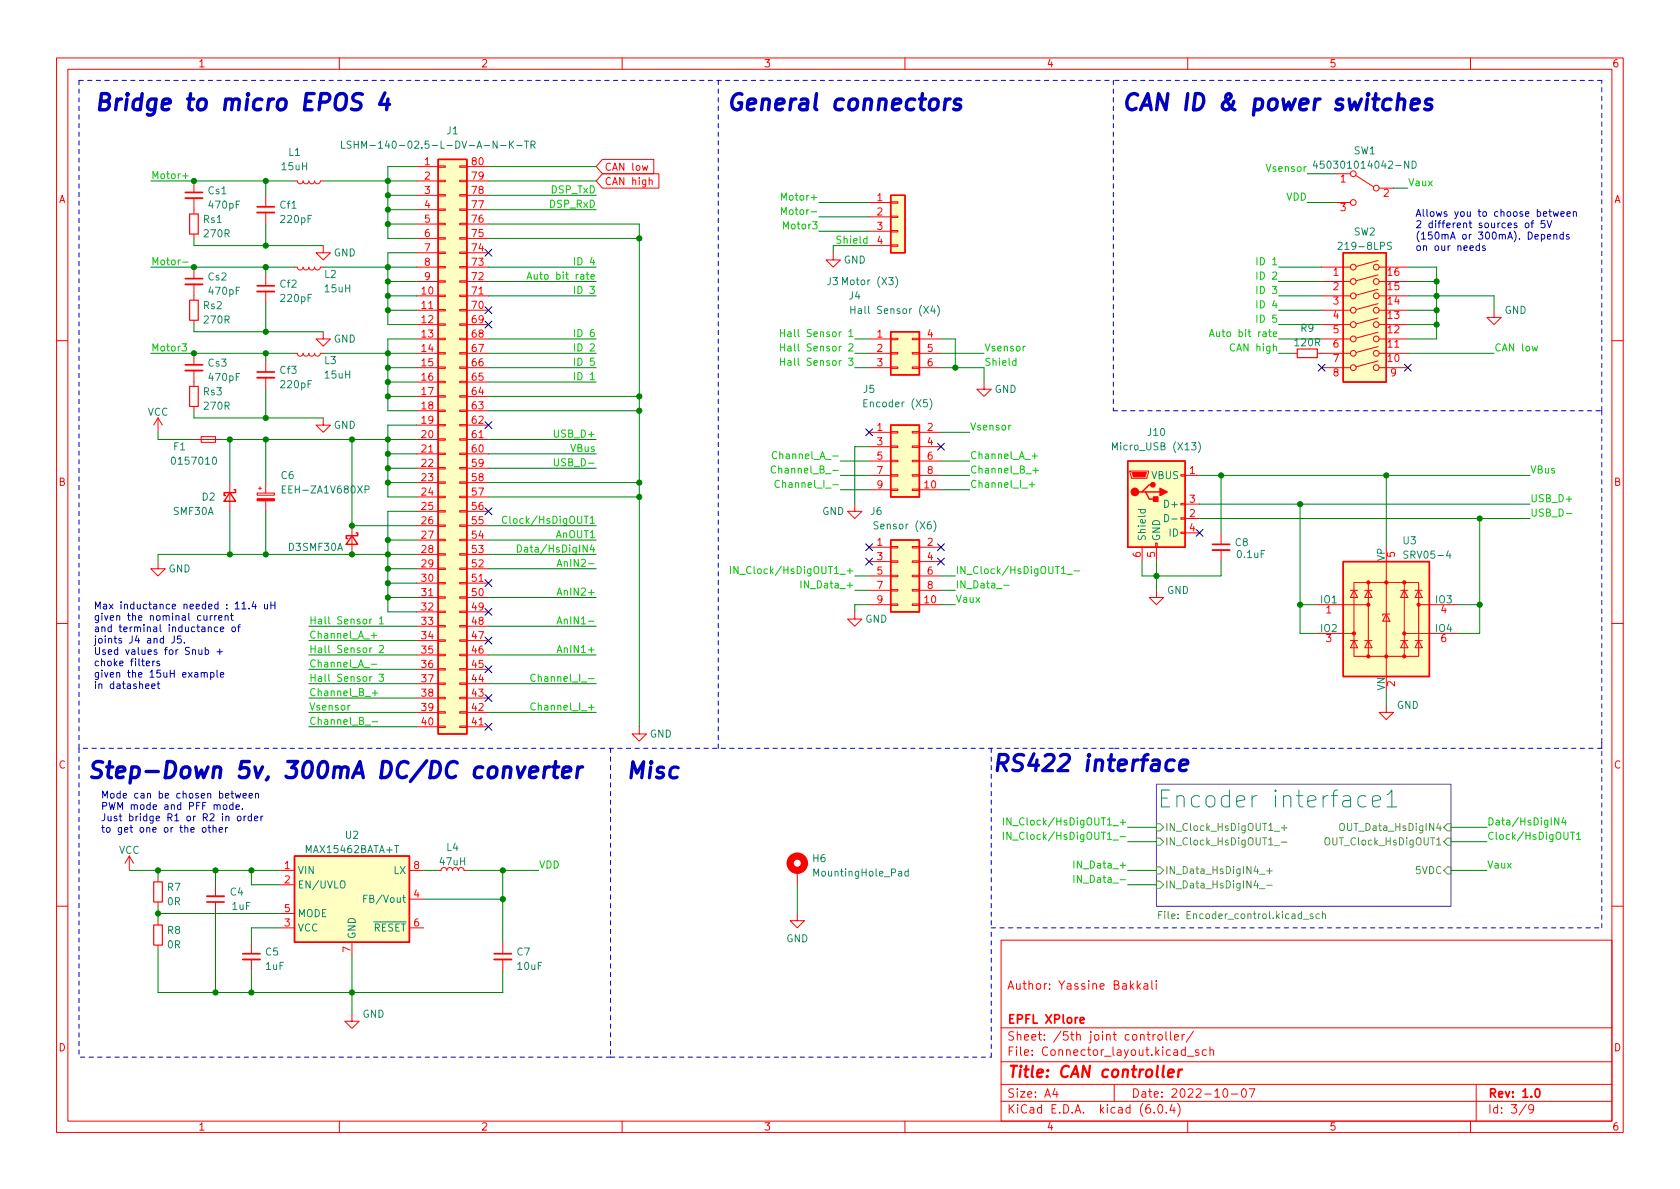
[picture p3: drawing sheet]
<svg xmlns="http://www.w3.org/2000/svg" width="297mm" height="210mm" viewBox="0 0 297 210" stroke-linecap="round" stroke-linejoin="round" font-family="sans-serif">
<defs><g id="words">
<text font-size="4.2" fill="#008484" x="207.3" y="142.8">Encoder interface1</text>
<g font-size="4" fill="#0000c2">
<text x="16.5" y="19.5">Bridge to micro EPOS 4</text>
<text x="128.3" y="19.5">General connectors</text>
<text x="198.1" y="19.5">CAN ID &amp; power switches</text>
<text x="15.2" y="137.7">Step-Down 5v, 300mA DC/DC converter</text>
<text x="110.5" y="137.7">Misc</text>
<text x="175.3" y="136.4">RS422 interface</text>
</g>
<text font-size="2.8" fill="#f00" x="178" y="190.6">Title: CAN controller</text>
<g font-size="2.1" fill="#f00">
<text x="178" y="175">Author: Yassine Bakkali</text>
<text x="178" y="184">Sheet: /5th joint controller/</text>
<text x="178" y="181">EPFL XPlore</text>
<text x="178" y="186.7">File: Connector_layout.kicad_sch</text>
<text x="178" y="196.9">KiCad E.D.A. kicad (6.0.4)</text>
<text x="178" y="194.1">Size: A4</text>
<text x="200" y="194.1">Date: 2022-10-07</text>
<text x="263" y="194.1">Rev: 1.0</text>
<text x="263" y="196.9">Id: 3/9</text>
</g>
<g font-size="1.8" fill="#f00">
<text x="35" y="11.9">1</text>
<text x="85" y="11.9">2</text>
<text x="135" y="11.9">3</text>
<text x="185" y="11.9">4</text>
<text x="235" y="11.9">5</text>
<text x="285" y="11.9">6</text>
<text x="75.1" y="29.2">1</text>
<text x="83.5" y="29.2">80</text>
<text x="10.3" y="35.9">A</text>
<text x="75.1" y="31.7">2</text>
<text x="75.1" y="34.3">3</text>
<text x="83.5" y="34.3">78</text>
<text x="83.5" y="31.7">79</text>
<text x="106.8" y="30.2">CAN low</text>
<text x="106.8" y="32.7">CAN high</text>
<text x="155.1" y="35.6">1</text>
<text x="237" y="32.3">1</text>
<text x="244.6" y="34.8">2</text>
<text x="285.3" y="35.9">A</text>
<text x="75.1" y="36.8">4</text>
<text x="75.1" y="39.4">5</text>
<text x="75.1" y="41.9">6</text>
<text x="83.5" y="41.9">75</text>
<text x="83.5" y="39.4">76</text>
<text x="83.5" y="36.8">77</text>
<text x="155.1" y="38.1">2</text>
<text x="155.1" y="40.6">3</text>
<text x="237" y="37.3">3</text>
<text x="75.1" y="44.4">7</text>
<text x="75.1" y="47">8</text>
<text x="83.5" y="47">73</text>
<text x="83.5" y="44.4">74</text>
<text x="155.1" y="43.2">4</text>
<text x="74.6" y="52.1">10</text>
<text x="75.1" y="49.5">9</text>
<text x="83.5" y="52.1">71</text>
<text x="83.5" y="49.5">72</text>
<text x="235.7" y="48.8">1</text>
<text x="235.7" y="51.3">2</text>
<text x="235.7" y="53.8">3</text>
<text x="245.4" y="53.8">14</text>
<text x="245.4" y="51.3">15</text>
<text x="245.4" y="48.8">16</text>
<text x="74.6" y="54.6">11</text>
<text x="74.6" y="57.1">12</text>
<text x="74.6" y="59.7">13</text>
<text x="83.5" y="59.7">68</text>
<text x="83.5" y="57.1">69</text>
<text x="83.5" y="54.6">70</text>
<text x="155.1" y="59.7">1</text>
<text x="164" y="59.7">4</text>
<text x="235.7" y="56.4">4</text>
<text x="235.7" y="58.9">5</text>
<text x="245.4" y="58.9">12</text>
<text x="245.4" y="56.4">13</text>
<text x="74.6" y="62.2">14</text>
<text x="74.6" y="64.8">15</text>
<text x="83.5" y="64.8">66</text>
<text x="83.5" y="62.2">67</text>
<text x="155.1" y="62.2">2</text>
<text x="155.1" y="64.8">3</text>
<text x="164" y="62.2">5</text>
<text x="164" y="64.8">6</text>
<text x="235.7" y="61.5">6</text>
<text x="235.7" y="64">7</text>
<text x="245.4" y="64">10</text>
<text x="245.4" y="61.5">11</text>
<text x="74.6" y="67.3">16</text>
<text x="74.6" y="69.8">17</text>
<text x="83.5" y="69.8">64</text>
<text x="83.5" y="67.3">65</text>
<text x="235.7" y="66.5">8</text>
<text x="245.9" y="66.5">9</text>
<text x="74.6" y="72.4">18</text>
<text x="74.6" y="74.9">19</text>
<text x="74.6" y="77.5">20</text>
<text x="83.5" y="77.5">61</text>
<text x="83.5" y="74.9">62</text>
<text x="83.5" y="72.4">63</text>
<text x="155.1" y="76.2">1</text>
<text x="164" y="76.2">2</text>
<text x="74.6" y="80">21</text>
<text x="74.6" y="82.5">22</text>
<text x="83.5" y="82.5">59</text>
<text x="83.5" y="80">60</text>
<text x="155.1" y="78.7">3</text>
<text x="155.1" y="81.3">5</text>
<text x="155.1" y="83.8">7</text>
<text x="164" y="78.7">4</text>
<text x="164" y="81.3">6</text>
<text x="164" y="83.8">8</text>
<text x="210.3" y="83.8">1</text>
<text x="10.3" y="85.9">B</text>
<text x="74.6" y="85.1">23</text>
<text x="74.6" y="87.6">24</text>
<text x="83.5" y="87.6">57</text>
<text x="83.5" y="85.1">58</text>
<text x="155.1" y="86.4">9</text>
<text x="163.5" y="86.4">10</text>
<text x="210.3" y="88.9">3</text>
<text x="285.3" y="85.9">B</text>
<text x="74.6" y="90.2">25</text>
<text x="74.6" y="92.7">26</text>
<text x="74.6" y="95.2">27</text>
<text x="83.5" y="95.2">54</text>
<text x="83.5" y="92.7">55</text>
<text x="83.5" y="90.2">56</text>
<text x="210.3" y="91.4">2</text>
<text x="210.3" y="94">4</text>
<text x="74.6" y="97.8">28</text>
<text x="74.6" y="100.3">29</text>
<text x="83.5" y="100.3">52</text>
<text x="83.5" y="97.8">53</text>
<text x="155.1" y="96.5">1</text>
<text x="155.1" y="99.1">3</text>
<text x="155.1" y="101.6">5</text>
<text x="164" y="96.5">2</text>
<text x="164" y="99.1">4</text>
<text x="164" y="101.6">6</text>
<text x="201.7" y="98.5" transform="rotate(-90 201.7 98.5)">6</text>
<text x="204.2" y="98.5" transform="rotate(-90 204.2 98.5)">5</text>
<text x="246.6" y="98.5" transform="rotate(-90 246.6 98.5)">5</text>
<text x="74.6" y="102.9">30</text>
<text x="74.6" y="105.4">31</text>
<text x="74.6" y="107.9">32</text>
<text x="83.5" y="107.9">49</text>
<text x="83.5" y="105.4">50</text>
<text x="83.5" y="102.9">51</text>
<text x="155.1" y="104.1">7</text>
<text x="155.1" y="106.7">9</text>
<text x="163.5" y="106.7">10</text>
<text x="164" y="104.1">8</text>
<text x="74.6" y="110.5">33</text>
<text x="74.6" y="113">34</text>
<text x="83.5" y="113">47</text>
<text x="83.5" y="110.5">48</text>
<text x="234.5" y="108.5">1</text>
<text x="234.5" y="113.5">3</text>
<text x="254.8" y="108.5">4</text>
<text x="254.8" y="113.5">6</text>
<text x="74.6" y="115.6">35</text>
<text x="74.6" y="118.1">36</text>
<text x="83.5" y="118.1">45</text>
<text x="83.5" y="115.6">46</text>
<text x="74.6" y="120.6">37</text>
<text x="74.6" y="123.2">38</text>
<text x="74.6" y="125.7">39</text>
<text x="83.5" y="125.7">42</text>
<text x="83.5" y="123.2">43</text>
<text x="83.5" y="120.6">44</text>
<text x="246.6" y="121.4" transform="rotate(-90 246.6 121.4)">2</text>
<text x="74.6" y="128.3">40</text>
<text x="83.5" y="128.3">41</text>
<text x="10.3" y="135.9">C</text>
<text x="285.3" y="135.9">C</text>
<text x="50.3" y="153.7">1</text>
<text x="73.2" y="153.7">8</text>
<text x="50.3" y="156.2">2</text>
<text x="50.3" y="161.3">5</text>
<text x="73.2" y="158.7">4</text>
<text x="50.3" y="163.8">3</text>
<text x="73.2" y="163.8">6</text>
<text x="62" y="168.4" transform="rotate(-90 62 168.4)">7</text>
<text x="10.3" y="185.9">D</text>
<text x="285.3" y="185.9">D</text>
<text x="35" y="199.9">1</text>
<text x="85" y="199.9">2</text>
<text x="135" y="199.9">3</text>
<text x="185" y="199.9">4</text>
<text x="235" y="199.9">5</text>
<text x="285" y="199.9">6</text>
</g>
<g font-size="1.8" fill="#008484">
<text x="79" y="23.7">J1</text>
<text x="51" y="27.6">L1</text>
<text x="64.5" y="26.3">LSHM-140-02.5-L-DV-A-N-K-TR</text>
<text x="233.8" y="29.8">450301014042-ND</text>
<text x="239.4" y="27.3">SW1</text>
<text x="36.8" y="34.3">Cs1</text>
<text x="49.9" y="30.1">15uH</text>
<text x="36" y="39.4">Rs1</text>
<text x="36.2" y="42">270R</text>
<text x="37.1" y="36.9">470pF</text>
<text x="49.6" y="36.9">Cf1</text>
<text x="49.8" y="39.4">220pF</text>
<text x="239.4" y="41.6">SW2</text>
<text x="59" y="45.3">GND</text>
<text x="149.2" y="46.6">GND</text>
<text x="237.3" y="44.2">219-8LPS</text>
<text x="36.8" y="49.6">Cs2</text>
<text x="37.1" y="52.1">470pF</text>
<text x="49.6" y="50.9">Cf2</text>
<text x="49.8" y="53.4">220pF</text>
<text x="57.4" y="49.1">L2</text>
<text x="57.5" y="51.7">15uH</text>
<text x="146.2" y="50.4">J3</text>
<text x="149.5" y="50.4">Motor (X3)</text>
<text x="150.1" y="53">J4</text>
<text x="36" y="54.7">Rs2</text>
<text x="36.2" y="57.2">270R</text>
<text x="151.7" y="55.5">Hall Sensor (X4)</text>
<text x="230" y="58.7">R9</text>
<text x="266" y="55.5">GND</text>
<text x="36.8" y="64.8">Cs3</text>
<text x="57.4" y="64.4">L3</text>
<text x="59" y="60.6">GND</text>
<text x="229" y="61.2">120R</text>
<text x="36" y="69.9">Rs3</text>
<text x="37.1" y="67.4">470pF</text>
<text x="49.6" y="66.1">Cf3</text>
<text x="49.8" y="68.6">220pF</text>
<text x="57.5" y="66.9">15uH</text>
<text x="152.7" y="69.5">J5</text>
<text x="175.8" y="69.5">GND</text>
<text x="26.1" y="73.5">VCC</text>
<text x="36.2" y="72.4">270R</text>
<text x="59" y="75.8">GND</text>
<text x="153.3" y="72">Encoder (X5)</text>
<text x="203" y="77.1">J10</text>
<text x="30.7" y="79.6">F1</text>
<text x="30.8" y="82.2">0157010</text>
<text x="197.3" y="79.6">Micro_USB (X13)</text>
<text x="35.7" y="88.5">D2</text>
<text x="49.7" y="84.7">C6</text>
<text x="50.5" y="87.2">EEH-ZA1V680XP</text>
<text x="203.6" y="84.7">VBUS</text>
<text x="206.2" y="89.8">D+</text>
<text x="30.7" y="91.1">SMF30A</text>
<text x="145.4" y="91.1">GND</text>
<text x="154" y="91.1">J6</text>
<text x="155.1" y="93.6">Sensor (X6)</text>
<text x="202.6" y="95.8" transform="rotate(-90 202.6 95.8)">Shield</text>
<text x="205.1" y="95.8" transform="rotate(-90 205.1 95.8)">GND</text>
<text x="206.8" y="94.9">ID</text>
<text x="29.8" y="101.2">GND</text>
<text x="51" y="97.4">D3 SMF30A</text>
<text x="218.4" y="96.6">C8</text>
<text x="218.8" y="98.7">0.1uF</text>
<text x="244.9" y="99.2" transform="rotate(-90 244.9 99.2)">VP</text>
<text x="248.1" y="96.2">U3</text>
<text x="248.8" y="98.8">SRV05-4</text>
<text x="206.3" y="105">GND</text>
<text x="233.5" y="106.7">IO1</text>
<text x="253.8" y="106.7">IO3</text>
<text x="153" y="110.1">GND</text>
<text x="233.5" y="111.8">IO2</text>
<text x="253.8" y="111.8">IO4</text>
<text x="244.9" y="122.1" transform="rotate(-90 244.9 122.1)">VN</text>
<text x="247" y="125.3">GND</text>
<text x="114.9" y="130.4">GND</text>
<text x="61.1" y="148.3">U2</text>
<text x="21" y="151">VCC</text>
<text x="52.6" y="154.6">VIN</text>
<text x="54.3" y="150.9">MAX15462BATA+T</text>
<text x="69.6" y="154.6">LX</text>
<text x="77.8" y="153">47uH</text>
<text x="79" y="150.5">L4</text>
<text x="143.7" y="152.4">H6</text>
<text x="144.2" y="155">MountingHole_Pad</text>
<text x="29.6" y="157.5">R7</text>
<text x="29.6" y="160.1">0R</text>
<text x="40.7" y="158.4">C4</text>
<text x="41.1" y="160.9">1uF</text>
<text x="52.6" y="157.1">EN/UVLO</text>
<text x="65.1" y="159.6">FB/Vout</text>
<text x="29.6" y="165.1">R8</text>
<text x="29.6" y="167.7">0R</text>
<text x="52.6" y="164.7">VCC</text>
<text x="52.6" y="162.2">MODE</text>
<text x="62.9" y="166.1" transform="rotate(-90 62.9 166.1)">GND</text>
<text x="64.6" y="164.7">~{RESET}</text>
<text x="139" y="166.6">GND</text>
<text x="47" y="169">C5</text>
<text x="47" y="171.5">1uF</text>
<text x="91.4" y="169">C7</text>
<text x="91.6" y="171.5">10uF</text>
<text x="64.1" y="180">GND</text>
</g>
<g font-size="1.8" fill="#00c200">
<text x="26.7" y="31.6">Motor+</text>
<text x="97.4" y="34.2">DSP_TxD</text>
<text x="138.8" y="35.5">Motor+</text>
<text x="224.2" y="30.4">Vsensor</text>
<text x="227.4" y="35.5">VDD</text>
<text x="248.9" y="32.9">Vaux</text>
<text x="97.3" y="36.7">DSP_RxD</text>
<text x="138.9" y="40.5">Motor3</text>
<text x="139.3" y="38">Motor-</text>
<text x="26.7" y="46.9">Motor-</text>
<text x="102.2" y="46.9">ID 4</text>
<text x="148.4" y="43.1">Shield</text>
<text x="222.8" y="46.9">ID 1</text>
<text x="95" y="49.4">Auto bit rate</text>
<text x="102.2" y="52">ID 3</text>
<text x="222.8" y="52">ID 3</text>
<text x="222.8" y="49.4">ID 2</text>
<text x="102.2" y="59.6">ID 6</text>
<text x="139.9" y="59.6">Hall Sensor 1</text>
<text x="215.6" y="59.6">Auto bit rate</text>
<text x="222.8" y="57">ID 5</text>
<text x="222.8" y="54.5">ID 4</text>
<text x="26.7" y="62.1">Motor3</text>
<text x="102.2" y="62.1">ID 2</text>
<text x="102.2" y="64.7">ID 5</text>
<text x="139.9" y="62.1">Hall Sensor 2</text>
<text x="139.9" y="64.7">Hall Sensor 3</text>
<text x="174" y="64.7">Shield</text>
<text x="174" y="62.1">Vsensor</text>
<text x="218" y="62.1">CAN high</text>
<text x="264.2" y="62.1">CAN low</text>
<text x="102.2" y="67.2">ID 1</text>
<text x="98.4" y="77.4">USB_D+</text>
<text x="171.4" y="76.1">Vsensor</text>
<text x="98.8" y="82.4">USB_D-</text>
<text x="100.9" y="79.9">VBus</text>
<text x="137.8" y="83.7">Channel_B_-</text>
<text x="137.8" y="81.2">Channel_A_-</text>
<text x="171.4" y="81.2">Channel_A_+</text>
<text x="171.4" y="83.7">Channel_B_+</text>
<text x="270.5" y="83.7">VBus</text>
<text x="138.6" y="86.3">Channel_I_-</text>
<text x="171.4" y="86.3">Channel_I_+</text>
<text x="270.5" y="88.8">USB_D+</text>
<text x="90.3" y="92.6">Clock/HsDigOUT1</text>
<text x="98.3" y="95.1">AnOUT1</text>
<text x="270.5" y="91.3">USB_D-</text>
<text x="93.2" y="97.7">Data/HsDigIN4</text>
<text x="99.7" y="100.2">AnIN2-</text>
<text x="131.2" y="101.5">IN_Clock/HsDigOUT1_+</text>
<text x="168.9" y="101.5">IN_Clock/HsDigOUT1_-</text>
<text x="99.3" y="105.3">AnIN2+</text>
<text x="142.5" y="104">IN_Data_+</text>
<text x="168.9" y="106.6">Vaux</text>
<text x="168.9" y="104">IN_Data_-</text>
<text x="54.6" y="110.4">Hall Sensor 1</text>
<text x="54.6" y="112.9">Channel_A_+</text>
<text x="99.7" y="110.4">AnIN1-</text>
<text x="54.6" y="115.5">Hall Sensor 2</text>
<text x="54.6" y="118">Channel_A_-</text>
<text x="99.3" y="115.5">AnIN1+</text>
<text x="54.6" y="120.5">Hall Sensor 3</text>
<text x="54.6" y="125.6">Vsensor</text>
<text x="54.6" y="123.1">Channel_B_+</text>
<text x="94.9" y="125.6">Channel_I_+</text>
<text x="95.4" y="120.5">Channel_I_-</text>
<text x="54.6" y="128.2">Channel_B_-</text>
<text x="179.5" y="145.9">IN_Clock/HsDigOUT1_+</text>
<text x="179.9" y="148.5">IN_Clock/HsDigOUT1_-</text>
<text x="262.9" y="148.5">Clock/HsDigOUT1</text>
<text x="262.9" y="145.9">Data/HsDigIN4</text>
<text x="95.2" y="153.6">VDD</text>
<text x="190.8" y="153.6">IN_Data_+</text>
<text x="262.9" y="153.6">Vaux</text>
<text x="191.2" y="156.1">IN_Data_-</text>
</g>
<g font-size="1.8" fill="#848400">
<text x="205.9" y="146.9">IN_Clock_HsDigOUT1_+</text>
<text x="205.9" y="149.5">IN_Clock_HsDigOUT1_-</text>
<text x="234.7" y="149.5">OUT_Clock_HsDigOUT1</text>
<text x="237.7" y="146.9">OUT_Data_HsDigIN4</text>
<text x="205.9" y="154.6">IN_Data_HsDigIN4_+</text>
<text x="250.4" y="154.6">5VDC</text>
<text x="205.9" y="157.1">IN_Data_HsDigIN4_-</text>
<text x="206" y="162.5">File: Encoder_control.kicad_sch</text>
</g>
<g font-size="1.7" fill="#0000c2">
<text x="250.2" y="38.3">Allows you to choose between</text>
<text x="250.2" y="40.3">2 different sources of 5V</text>
<text x="250.2" y="42.3">(150mA or 300mA). Depends</text>
<text x="250.2" y="44.4">on our needs</text>
<text x="16.5" y="107.7">Max inductance needed : 11.4 uH</text>
<text x="16.5" y="109.7">given the nominal current</text>
<text x="16.5" y="111.8">and terminal inductance of</text>
<text x="16.5" y="113.8">joints J4 and J5.</text>
<text x="16.5" y="115.8">Used values for Snub +</text>
<text x="16.5" y="117.8">choke filters</text>
<text x="16.5" y="119.8">given the 15uH example</text>
<text x="16.5" y="121.8">in datasheet</text>
<text x="17.8" y="141.2">Mode can be chosen between</text>
<text x="17.8" y="143.2">PWM mode and PFF mode.</text>
<text x="17.8" y="145.2">Just bridge R1 or R2 in order</text>
<text x="17.8" y="147.2">to get one or the other</text>
</g>
</g></defs>
<g fill="none" stroke="#f00" stroke-width=".18">
<path d="M10 10.2h277v190.1h-277zM12 12.2h273v186.1h-273zM60 10.2v2M110 10.2v2M160 10.2v2M210 10.2v2M260 10.2v2M34.3 32v2M34.3 35v2.8M47 34.5v2.1M47 37.6v2M52.1 32h.5l.1 .4 .4 .1 .3-.1 .2-.4 .1 .3 .3 .2 .4-.1 .2-.4 .2 .4 .5 .1 .2-.2 .1-.3 .2 .4 .3 .1 .4-.1 .1-.4h.5"/>
<path d="M73.7 32h3.8M73.7 29.5h3.8M73.7 34.5h3.8M73.7 37.1h3.8M73.7 39.6h3.8M77.5 39.5h1.2v.2h-1.2zM77.5 37h1.2v.2h-1.2zM77.5 34.4h1.2v.3h-1.2zM77.5 31.9h1.2v.2h-1.2zM77.5 29.3h1.2v.3h-1.2zM81.3 39.5h1.2v.2h-1.2zM81.3 37h1.2v.2h-1.2z"/>
<path d="M81.3 34.4h1.2v.3h-1.2zM81.3 31.9h1.2v.2h-1.2zM81.3 29.3h1.2v.3h-1.2zM82.5 32h3.9M82.5 29.5h3.9M82.5 34.5h3.9M82.5 37.1h3.9M82.5 39.6h3.9M106.5 28.2h9.1v2.5h-9.1l-1.1-1.2zM106.5 30.7h10v2.6h-10l-1.1-1.3zM113.6 29.3l.2 .8 .3-.6 .2 .6 .2-.8M114.8 31.9l.2-.1 .3 .1v.8"/>
<path d="M153.7 35.8h3.8M153.7 38.3h3.8M157.5 38.2h1.2v.3h-1.2zM157.5 35.7h1.2v.2h-1.2zM236.2 30.7h2.6M236.2 35.8h2.6M239.6 31l3.2 2M243.8 33.3h2.6M34.3 41.4v.8M34.3 47.2v2.1M34.3 50.3v2.8M34.3 56.6v.8"/>
<path d="M47 48.5v2M47 51.6v2M52.1 47.2h.5l.1 .4 .4 .1 .3-.1 .2-.4 .1 .4 .3 .1 .4-.1 .2-.4 .2 .4 .5 .1 .2-.1 .1-.4 .2 .4 .3 .1 .4-.1 .1-.4h.5M57.1 43.4v1.3h1.3l-1.3 1.3-1.2-1.3h1.2M57.1 58.7v1.2h1.3l-1.3 1.3-1.2-1.3h1.2M73.7 47.2h3.8M73.7 52.3h3.8M73.7 54.9h3.8M73.7 57.4h3.8M73.7 59.9h3.8M73.7 42.2h3.8M73.7 44.7h3.8"/>
<path d="M73.7 49.8h3.8M77.5 59.8h1.2v.3h-1.2zM77.5 57.3h1.2v.2h-1.2zM77.5 54.7h1.2v.3h-1.2zM77.5 52.2h1.2v.2h-1.2zM77.5 49.7h1.2v.2h-1.2zM77.5 47.1h1.2v.3h-1.2zM77.5 44.6h1.2v.2h-1.2zM77.5 42h1.2v.3h-1.2zM81.3 59.8h1.2v.3h-1.2zM81.3 57.3h1.2v.2h-1.2zM81.3 54.7h1.2v.3h-1.2z"/>
<path d="M81.3 52.2h1.2v.2h-1.2zM81.3 49.7h1.2v.2h-1.2zM81.3 47.1h1.2v.3h-1.2zM81.3 44.6h1.2v.2h-1.2zM81.3 42h1.2v.3h-1.2zM82.5 47.2h3.9M82.5 52.3h3.9M82.5 54.9h3.9M82.5 57.4h3.9M82.5 59.9h3.9M82.5 42.2h3.9M82.5 44.7h3.9"/>
<path d="M82.5 49.8h3.9M147.3 44.7v1.3h1.3l-1.3 1.2-1.3-1.2h1.3M153.7 59.9h3.8M153.7 40.9h3.8M153.7 43.4h3.8M157.5 59.8h1.2v.3h-1.2zM157.5 43.3h1.2v.3h-1.2zM157.5 40.8h1.2v.2h-1.2zM161.3 59.8h1.3v.3h-1.3zM162.6 59.9h3.8M233.7 47.2h5.1M233.7 52.3h5.1"/>
<path d="M233.7 54.9h5.1M233.7 57.4h5.1M233.7 59.9h5.1M233.7 49.8h5.1M243.7 58.7l-3.9 1.1M243.7 56.2l-3.9 1.1M243.7 53.7l-3.9 1M243.7 51.1l-3.9 1.1M243.7 48.6l-3.9 1.1M243.7 46.1l-3.9 1M243.8 47.2h5.1M243.8 52.3h5.1"/>
<path d="M243.8 54.9h5.1M243.8 57.4h5.1M243.8 59.9h5.1M243.8 49.8h5.1M264.2 54.9v1.2h1.2l-1.2 1.3-1.3-1.3h1.3M10 60.2h2M27.9 73.9l-.7 1.3M27.9 73.9v2.5M27.9 73.9l.8 1.3M34.3 77.7h5.1M34.3 62.5v2M34.3 65.5v2.8"/>
<path d="M34.3 71.9v.7M35.6 77.2h2.5v1h-2.5zM47 63.7v2.1M47 66.8v2M52.1 62.5h.5l.1 .3 .4 .2 .3-.2 .2-.3 .1 .3 .3 .2 .4-.1 .2-.4 .2 .4 .5 .1 .2-.2 .1-.3 .2 .3 .3 .2 .4-.2 .1-.3h.5M57.1 73.9v1.3h1.3l-1.3 1.2-1.2-1.2h1.2M73.7 62.5h3.8M73.7 77.7h3.8M73.7 65h3.8M73.7 67.6h3.8M73.7 70.1h3.8M73.7 72.6h3.8"/>
<path d="M73.7 75.2h3.8M77.5 77.6h1.2v.2h-1.2zM77.5 75.1h1.2v.2h-1.2zM77.5 72.5h1.2v.3h-1.2zM77.5 70h1.2v.2h-1.2zM77.5 67.4h1.2v.3h-1.2zM77.5 64.9h1.2v.2h-1.2zM77.5 62.4h1.2v.2h-1.2zM81.3 77.6h1.2v.2h-1.2zM81.3 75.1h1.2v.2h-1.2zM81.3 72.5h1.2v.3h-1.2zM81.3 70h1.2v.2h-1.2z"/>
<path d="M81.3 67.4h1.2v.3h-1.2zM81.3 64.9h1.2v.2h-1.2zM81.3 62.4h1.2v.2h-1.2zM82.5 62.5h3.9M82.5 77.7h3.9M82.5 65h3.9M82.5 67.6h3.9M82.5 70.1h3.9M82.5 72.6h3.9M82.5 75.2h3.9M153.7 76.4h3.8M153.7 79h3.8"/>
<path d="M153.7 62.5h3.8M153.7 65h3.8M157.5 78.9h1.2v.2h-1.2zM157.5 76.3h1.2v.3h-1.2zM157.5 64.9h1.2v.2h-1.2zM157.5 62.4h1.2v.2h-1.2zM161.3 78.9h1.3v.2h-1.3zM161.3 76.3h1.3v.3h-1.3zM161.3 64.9h1.3v.2h-1.3zM161.3 62.4h1.3v.2h-1.3zM162.6 76.4h3.8M162.6 79h3.8"/>
<path d="M162.6 62.5h3.8M162.6 65h3.8M174 67.6v1.2h1.3l-1.3 1.3-1.3-1.3h1.3M228.6 62.5h.8M232.9 62.5h5.9M233.7 65h5.1M243.7 63.8l-3.9 1.1M243.7 61.3l-3.9 1M243.8 62.5h5.1M243.8 65h5.1M285 60.2h2M27.9 99.3v1.3h1.3l-1.3 1.2-1.2-1.2h1.2"/>
<path d="M40.6 85.3v5.1M45.5 87.2h3v.4h-3zM45.7 86.4h.5M46 86.1v.5M47 85.3v1.9M47 88.6v1.8M62.2 93v5M73.7 80.3h3.8M73.7 82.8h3.8M73.7 85.3h3.8M73.7 87.9h3.8M73.7 90.4h3.8"/>
<path d="M73.7 93h3.8M73.7 95.5h3.8M73.7 98h3.8M77.5 97.9h1.2v.3h-1.2zM77.5 95.4h1.2v.2h-1.2zM77.5 92.8h1.2v.3h-1.2zM77.5 90.3h1.2v.2h-1.2zM77.5 87.8h1.2v.2h-1.2zM77.5 85.2h1.2v.3h-1.2zM77.5 82.7h1.2v.2h-1.2zM77.5 80.1h1.2v.3h-1.2zM81.3 97.9h1.2v.3h-1.2z"/>
<path d="M81.3 95.4h1.2v.2h-1.2zM81.3 92.8h1.2v.3h-1.2zM81.3 90.3h1.2v.2h-1.2zM81.3 87.8h1.2v.2h-1.2zM81.3 85.2h1.2v.3h-1.2zM81.3 82.7h1.2v.2h-1.2zM81.3 80.1h1.2v.3h-1.2zM82.5 80.3h3.9M82.5 82.8h3.9M82.5 85.3h3.9M82.5 87.9h3.9M82.5 90.4h3.9"/>
<path d="M82.5 93h3.9M82.5 95.5h3.9M82.5 98h3.9M151.1 89.1v1.3h1.3l-1.3 1.3-1.2-1.3h1.2M153.7 86.6h3.8M153.7 81.5h3.8M153.7 84.1h3.8M153.7 96.8h3.8M153.7 99.3h3.8M157.5 86.5h1.2v.2h-1.2zM157.5 83.9h1.2v.3h-1.2zM157.5 81.4h1.2v.3h-1.2z"/>
<path d="M157.5 99.2h1.2v.2h-1.2zM157.5 96.6h1.2v.3h-1.2zM161.3 86.5h1.3v.2h-1.3zM161.3 83.9h1.3v.3h-1.3zM161.3 81.4h1.3v.3h-1.3zM161.3 99.2h1.3v.2h-1.3zM161.3 96.6h1.3v.3h-1.3zM162.6 86.6h3.8M162.6 81.5h3.8M162.6 84.1h3.8M162.6 96.8h3.8M162.6 99.3h3.8"/>
<path d="M199.8 83.3h3.3v.3l-.3 1h-2.8zM201.9 96.8v2.5M204.3 96h.3v.8h-.3zM204.5 96.8v2.5M208.8 94.1h.7v.3h-.7zM208.8 91.6h.7v.2h-.7zM208.8 89h.7v.3h-.7zM208.8 83.9h.7v.3h-.7zM209.5 84.1h2.6M209.5 91.7h2.6M209.5 89.1h2.6M209.5 94.2h2.6"/>
<path d="M215.9 94.2v2.1M215.9 97.3v2M245.1 99.3v20.3M10 110.2h2M73.7 113.3h3.8M73.7 100.6h3.8M73.7 103.1h3.8M73.7 105.7h3.8M73.7 108.2h3.8M73.7 110.7h3.8M73.7 115.8h3.8M73.7 118.4h3.8"/>
<path d="M77.5 118.2h1.2v.3h-1.2zM77.5 115.7h1.2v.2h-1.2zM77.5 113.2h1.2v.2h-1.2zM77.5 110.6h1.2v.3h-1.2zM77.5 108.1h1.2v.2h-1.2zM77.5 105.5h1.2v.3h-1.2zM77.5 103h1.2v.2h-1.2zM77.5 100.5h1.2v.2h-1.2zM81.3 118.2h1.2v.3h-1.2zM81.3 115.7h1.2v.2h-1.2zM81.3 113.2h1.2v.2h-1.2zM81.3 110.6h1.2v.3h-1.2z"/>
<path d="M81.3 108.1h1.2v.2h-1.2zM81.3 105.5h1.2v.3h-1.2zM81.3 103h1.2v.2h-1.2zM81.3 100.5h1.2v.2h-1.2zM82.5 113.3h3.9M82.5 100.6h3.9M82.5 103.1h3.9M82.5 105.7h3.9M82.5 108.2h3.9M82.5 110.7h3.9M82.5 115.8h3.9M82.5 118.4h3.9"/>
<path d="M151.1 108.2v1.3h1.3l-1.3 1.2-1.2-1.2h1.2M153.7 106.9h3.8M153.7 101.8h3.8M153.7 104.4h3.8M157.5 106.8h1.2v.3h-1.2zM157.5 104.3h1.2v.2h-1.2zM157.5 101.7h1.2v.3h-1.2zM161.3 106.8h1.3v.3h-1.3zM161.3 104.3h1.3v.2h-1.3zM161.3 101.7h1.3v.3h-1.3zM162.6 106.9h3.8M162.6 101.8h3.8"/>
<path d="M162.6 104.4h3.8M204.5 104.4v1.3h1.2l-1.2 1.2-1.3-1.2h1.3M232.4 106.9h9.5M232.4 112h7M238.8 104.4h1.2M238.8 113.3h1.2M239.4 103h11.4v13.1h-11.4zM239.4 113.3l.6 1.2h-1.2zM239.4 104.4l.6 1.3h-1.2zM241.3 104.4h1.3M241.3 113.3h1.3M241.9 113.3l.7 1.2h-1.3z"/>
<path d="M241.9 104.4l.7 1.3h-1.3zM241.9 103v13.1M245.1 108.6l.6 1.2h-1.2zM245.7 108.6h-1.2v.2M247.6 104.4h1.3M247.6 113.3h1.3M248.3 113.3l.6 1.2h-1.3zM248.3 104.4l.6 1.3h-1.3zM248.3 103v13.1M248.3 112h9.5M250.2 104.4h1.3M250.2 113.3h1.3"/>
<path d="M250.8 113.3l.7 1.2h-1.3zM250.8 104.4l.7 1.3h-1.3zM250.8 106.9h7M285 110.2h2M73.7 120.9h3.8M73.7 123.4h3.8M73.7 126h3.8M73.7 128.5h3.8M77.5 128.4h1.2v.2h-1.2zM77.5 125.9h1.2v.2h-1.2zM77.5 123.3h1.2v.3h-1.2zM77.5 120.8h1.2v.2h-1.2z"/>
<path d="M81.3 128.4h1.2v.2h-1.2zM81.3 125.9h1.2v.2h-1.2zM81.3 123.3h1.2v.3h-1.2zM81.3 120.8h1.2v.2h-1.2zM82.5 120.9h3.9M82.5 123.4h3.9M82.5 126h3.9M82.5 128.5h3.9M113 128.5v1.3h1.3l-1.3 1.3-1.2-1.3h1.2M245.1 124.7v1.3h1.3l-1.3 1.2-1.3-1.2h1.3M22.9 151.4l-.8 1.2M22.9 151.4v2.5"/>
<path d="M22.9 151.4l.7 1.2M27.9 155.2v.8M27.9 159.5v.8M38.1 156.5v2M38.1 159.5v2M49.5 153.9h2.6M49.5 156.5h2.6M72.4 153.9h2.5M72.4 159h2.5M77.5 153.9h.5l.1-.3 .4-.2 .3 .2 .2 .3 .1-.3 .3-.2 .4 .1 .2 .4 .2-.4 .4-.1 .3 .2 .1 .3 .2-.3 .3-.2 .4 .2 .1 .3h.5M141 153.9v2.6M10 160.2h2"/>
<path d="M27.9 162.8v.8M27.9 167.1v.8M44.4 166.6v2.1M44.4 169.7v2M49.5 164.1h2.6M49.5 161.5h2.6M62.2 179.3v1.3h1.3l-1.3 1.3-1.2-1.3h1.2M62.2 166.6v2.6M72.4 164.1h2.5M88.9 166.6v2.1M88.9 169.7v2M141 161.5v1.3h1.2l-1.2 1.3-1.3-1.3h1.3"/>
<path d="M177 166.3h108v32h-108zM201.1 173.4v1.5M201.2 174.4l.4 .5M201.6 173.9l-.5 .6M202.3 174h.6v.9M202.9 174.3l-.5 .1a.29 .29 0 0 0-.2 .2 .29 .29 0 0 0 .2 .3h.5M203.6 173.4v1.3l.3 .2M204.4 173.4v.2M204.4 173.9v1M285 160.2h2M60 198.3v2M110 198.3v2"/>
<path d="M160 198.3v2M177 194.8h108M177 191.8h108M177 187.8h108M177 181.8h108M186.5 192.5l-.4 1h1M186.9 193v1M197 191.8v3M202.8 182.9h.6M203 182.4v1.3l.4 .2M203.9 182.9v1M204.1 196.7v.1"/>
<path d="M204.3 182.9l-.3 .1-.1 .2M204.8 183.1l.2-.2 .4 .2 .1 .5-.1 .3h-.4l-.2-.1zM204.9 195.4l.2-.1a.81 .81 0 0 1 .6 .7 .81 .81 0 0 1-.3 .8h-.2a.81 .81 0 0 1-.6-.6 .81 .81 0 0 1 .3-.8zM206.1 182.4v1.3l.3 .2M206.2 196.7v.1M206.9 182.4v1.3l.2 .2M207.2 195.3l-.3 1h.9M207.6 195.8v1M207.6 183.4l.8-.1-.1-.3-.4-.1-.3 .2 .1 .8h.6M208.2 195.1a1.72 1.72 0 0 1 0 2.3M209 182.9v1M209.4 182.9l-.3 .1-.1 .2"/>
<path d="M209.6 185.7l-.5-.1-.2 .3v.4l.1 .3h.6M209.6 185.1v1.5M209.9 186.8h1.2M210 198.3v2M211 182.4l-1.3 1.9M211.9 185.7l-.3-.1-.2 .2v.3l.5 .1v.4h-.5M213.3 185.7l-.4-.1-.3 .3v.4l.1 .3h.6M213.9 185.8l.2-.2 .4 .1 .1 .9M213.9 185.1v1.5M216.4 192.6l.2-.1a.81 .81 0 0 1 .6 .7 .81 .81 0 0 1-.3 .8h-.2a.81 .81 0 0 1-.6-.6 .81 .81 0 0 1 .3-.8zM217.7 193.5h1.2M219.7 192.6l.2-.1a.81 .81 0 0 1 .5 .7 .81 .81 0 0 1-.3 .8h-.1a.81 .81 0 0 1-.6-.6 .81 .81 0 0 1 .3-.8z"/>
<path d="M220.9 192.5h1l-.7 1.5M260 198.3v2M261 191.8v6.5M269.9 195.3l-1.3 1.9M271.2 196l-.3 .3h-.3l-.3-.3 .1-.6 .5-.1 .2 .2a.99 .99 0 0 1-.4 1.3h-.3"/>
<circle cx="239.3" cy="30.7" r=".51"/>
<circle cx="239.3" cy="35.8" r=".51"/>
<circle cx="243.3" cy="33.3" r=".51"/>
<circle cx="239.3" cy="59.9" r=".51"/>
<circle cx="239.3" cy="54.9" r=".51"/>
<circle cx="239.3" cy="52.3" r=".51"/>
<circle cx="239.3" cy="49.8" r=".51"/>
<circle cx="239.3" cy="57.4" r=".51"/>
<circle cx="239.3" cy="47.2" r=".51"/>
<circle cx="243.3" cy="54.9" r=".51"/>
<circle cx="243.3" cy="52.3" r=".51"/>
<circle cx="243.3" cy="47.2" r=".51"/>
<circle cx="243.3" cy="49.8" r=".51"/>
<circle cx="243.3" cy="59.9" r=".51"/>
<circle cx="243.3" cy="57.4" r=".51"/>
<circle cx="239.3" cy="65" r=".51"/>
<circle cx="239.3" cy="62.5" r=".51"/>
<circle cx="243.3" cy="65" r=".51"/>
<circle cx="243.3" cy="62.5" r=".51"/>
</g>
<path d="M32.8 34h3M45.5 36.6h3M32.8 49.3h3M45.5 50.5h3M32.8 64.5h3M45.5 65.8h3M214.4 96.3h3M36.6 159.5h3M42.9 168.7h3.1M87.4 168.7h3M191 180.4l.7-.1-.1-.3-.4-.1-.2 .2 .1 .8h.5M271.6 192.6l.2-.1a.82 .82 0 0 1 .6 .7 .82 .82 0 0 1-.3 .8h-.2a.81 .81 0 0 1-.6-.6 .81 .81 0 0 1 .3-.8z" fill="none" stroke="#f00" stroke-width=".3"/>
<path d="M206.5 189.8l1-.2v-.4l-.2-.1-.6 .1-.2 1 .3 .3 .5-.1M208.4 189.1l-.1 1.4M209 189.1l-.4 .1-.2 .3" fill="none" stroke="#f00" stroke-width=".4"/>
<path d="M204.5 138.7h52v21.6h-52z" fill="#fff" stroke="#fff" stroke-width=".18"/>
<path d="M204.5 138.7h52v21.6h-52z" fill="none" stroke="#840084" stroke-width=".18"/>
<g fill="none" stroke="#848400" stroke-width=".18">
<path d="M204.5 145.7h.6l.6 .6-.6 .6h-.6zM204.5 148.2h.6l.6 .6-.6 .7h-.6zM204.5 153.3h.6l.6 .6-.6 .7h-.6zM204.5 155.8h.6l.6 .7-.6 .6h-.6zM222.7 154.6h1M222.7 157.2h1M224 154h.9M224 156.5h.9M224.5 153.5v1M225.3 147h1M225.3 149.5h1M226.6 146.4h.9"/>
<path d="M226.6 148.9h.9M227.1 145.9v1M236.9 145.8l.3-.2a.43 .43 0 0 1 .5 .4v.4a.42 .42 0 0 1-.4 .5 .42 .42 0 0 1-.4-.5zM254 149.4h.8M255.9 145.7h.6v1.2h-.6l-.6-.6zM255.9 153.3h.6v1.3h-.6l-.6-.7zM255.9 148.2h.6v1.3h-.6l-.6-.7zM204.9 161.8h.4M205.5 161.2h-.6v1.2M232.1 161.7l-.3-.1-.2 .2 .1 .2 .4 .1v.3h-.5M233.3 161.7l-.4-.1-.2 .2 .1 .6h.5M233.8 161.7l.2-.1 .3 .1 .1 .7"/>
<path d="M233.8 161.2v1.2"/>
</g>
<g fill="none" stroke="#008484" stroke-width=".18">
<path d="M60.4 24.9v1.3h.6M62.1 25l-.5-.1-.2 .2v.3l.6 .3 .1 .3-.3 .2h-.4M62.6 24.9v1.3M62.6 25.6h.7M63.3 24.9v1.3M64 26.2v-1.3l.4 1 .4-1v1.3M90.3 25.5l.5 .7M90.8 24.9l-.7 .8M91.3 25.7h1M92.7 24.9h.8M93.1 24.9v1.3M93.9 25.6h.6l.1-.2v-.3l-.7-.2v1.3"/>
<path d="M94.2 25.6l.4 .6M232.5 28.4l-.3 .9h.8M232.8 28.9v.9M249.7 28.5a.64 .64 0 0 1 .7 .6 .64 .64 0 0 1-.7 .7zM149 50.4v-1.3l.4 .9 .4-.9v1.3M150.4 54.2v1.2M150.4 54.8h.8M151.2 54.2v1.2M158.3 48.9a1.46 1.46 0 0 1 0 1.9M164.9 54.1l-.3 .9h.8M165.7 54a1.46 1.46 0 0 1 0 1.9M236.6 43l.5-.2 .2 .4-.8 .9h.8"/>
<path d="M246 42.9l-.5-.1-.1 .2v.3l.5 .3 .1 .3-.2 .2-.5-.1M152.7 71.3h.5M153.3 70.7h-.6v1.2h.6M164.4 70.5a1.46 1.46 0 0 1 0 1.9M196.7 79.6v-1.3l.4 .9 .4-.9v1.3M211.9 78.1a1.46 1.46 0 0 1 0 1.9M49.9 86.5h.4M50.5 85.9h-.6v1.3h.6M64.5 86.6l.7-.1 .1-.2-.1-.3-.7-.1v1.3M155.2 92.3h-.4l-.2 .1v.3l.5 .3 .1 .3-.2 .2h-.5M165.1 92.1a1.46 1.46 0 0 1 0 1.9M201.2 90.1h1.3"/>
<path d="M201.7 90.1v.4l.2 .2 .5-.1v-.5M205.9 91a.64 .64 0 0 1 .7 .6 .64 .64 0 0 1-.7 .7zM207.2 91.8h1M248.9 97.5l-.5-.1-.1 .2v.3l.5 .3 .1 .3-.2 .2h-.5M256.1 97.4l-.3 .9h.7M206.8 139.7h-1.4v3h1.4M60.2 155.9l.3-.1a.43 .43 0 0 1 .5 .4v.4a.42 .42 0 0 1-.4 .5 .42 .42 0 0 1-.4-.5zM64.3 158.9h.4M64.9 158.3h-.6v1.3M69.8 149.5h.7M160.6 154.1h-.4l-.2 .2 .1 .6h.5M160.6 153.7v1.2"/>
<path d="M205.4 141.1h1M242.7 141.7l1.4-.3-.2-.6-.2-.1h-.6l-.3 .1-.1 .3v1.2l.1 .3 .3 .1h.6l.2-.1M245.2 140.6l.3-.2 .6-.7v3M245.2 142.7h1.7"/>
</g>
<g fill="#ffffc2" stroke="#ffffc2" stroke-width=".18">
<path d="M157.5 75.2h5.1v12.7h-5.1z"/>
<path d="M157.5 95.5h5.1v12.7h-5.1z"/>
<path d="M237.5 99.3h15.2v20.3h-15.2z"/>
<path d="M77.5 28.2h5v101.6h-5z"/>
<path d="M157.5 58.7h5.1v7.6h-5.1z"/>
<path d="M199.4 81.5h10.1v15.3h-10.1z"/>
<path d="M237.5 44.7h7.6v22.9h-7.6z"/>
<path d="M157.5 34.5h2.5v10.2h-2.5z"/>
<path d="M52.1 151.4h20.3v15.2h-20.3z"/>
</g>
<g fill="none" stroke="#f00" stroke-width=".25">
<path d="M77.5 28.2h5v101.6h-5zM157.5 34.5h2.5v10.2h-2.5zM157.5 58.7h5.1v7.6h-5.1zM237.5 44.7h7.6v22.9h-7.6zM157.5 75.2h5.1v12.7h-5.1zM40.6 87.1l1.1 1.5h-2.1zM41.4 86.6h.3v.5h-2.1v.5h.3M62.2 94.7l1 1.6h-2zM63 94.2h.2v.5h-2v.5h.3M157.5 95.5h5.1v12.7h-5.1zM199.4 81.5h10.1v15.3h-10.1zM201.9 87h.7l.6 1.3h1.3"/>
<path d="M202.6 87h2.5M203.8 85.7h-.6l-1.3 1.3h-.6M237.5 99.3h15.2v20.3h-15.2zM52.1 151.4h20.3v15.2h-20.3z"/>
</g>
<path d="M33.5 37.8h1.6v3.6h-1.6zM33.5 53.1h1.6v3.5h-1.6zM33.5 68.3h1.6v3.6h-1.6zM229.4 61.7h3.5v1.5h-3.5zM27.2 156h1.5v3.5h-1.5zM27.2 163.6h1.5v3.5h-1.5z" fill="none" stroke="#f00" stroke-width=".2"/>
<g fill="#f00" stroke="#f00" stroke-width=".18">
<path d="M45.5 88.2h3v.4h-3z"/>
<path d="M200.2 83.6h2.5l-.3 .7h-2z"/>
<circle cx="239.4" cy="112" r=".28"/>
<circle cx="241.9" cy="116.1" r=".28"/>
<circle cx="241.9" cy="106.9" r=".28"/>
<circle cx="241.9" cy="103" r=".28"/>
<circle cx="245.1" cy="116.1" r=".28"/>
<circle cx="245.1" cy="103" r=".28"/>
<circle cx="248.3" cy="116.1" r=".28"/>
<circle cx="248.3" cy="112" r=".28"/>
<circle cx="248.3" cy="103" r=".28"/>
<circle cx="250.8" cy="106.9" r=".28"/>
</g>
<path d="M32.8 35h3M45.5 37.6h3M32.8 50.3h3M45.5 51.6h3M32.8 65.5h3M45.5 66.8h3M214.4 97.3h3M36.6 158.5h3M42.9 169.7h3.1M87.4 169.7h3" fill="none" stroke="#f00" stroke-width=".33"/>
<g fill="#f00" stroke="#f00" stroke-width=".25">
<path d="M205.1 86.4l1.3 .6-1.3 .6z"/>
<path d="M204 87.9h.7v.7h-.7z"/>
<circle cx="200.7" cy="87" r=".63"/>
<circle cx="203.8" cy="85.7" r=".38"/>
</g>
<circle cx="141" cy="152.6" r="1.27" fill="none" stroke="#f00" stroke-width="1.3"/>
<g fill="none" stroke="#00c200" stroke-width=".18">
<path d="M32.3 31.1h1M32.8 30.6v1M138.2 37.9v-1.2l.4 .9 .4-.9v1.2M138.2 35.4v-1.3l.4 .9 .4-.9v1.3M32.3 46.3h1M93.2 49.4l.4-1.3 .4 1.3M93.3 49h.6M101.6 45.6v1.2M101.6 50.6v1.3M101.6 58.3v1.2M104.5 48.9l.6-.1-.1-.2-.3-.1-.2 .2v.6h.5M138 58.3v1.2"/>
<path d="M138 58.9h.7M138.7 58.3v1.2M139.3 58.7h.5l.1 .8M139.9 59h-.5l-.1 .2 .1 .3h.5M150.1 59.5h.7M213.8 59.5l.5-1.2 .4 1.2M213.9 59.2h.7M222.2 45.6v1.2M222.2 48.1v1.3M222.2 50.6v1.3M222.2 53.2v1.2M222.2 55.7v1.3"/>
<path d="M225.1 59.1l.6-.1v-.3h-.4l-.2 .2 .1 .6h.5M32.2 60.8h.8l-.4 .5 .3 .1v.5l-.2 .2-.5-.2M101.6 60.8v1.3M101.6 63.3v1.3M101.6 65.9v1.2M137.3 80a.6 .6 0 0 0-.8 .4 .6 .6 0 0 0 .6 .7l.2-.1M138 60.8v1.3M138 63.3v1.3M138 61.4h.7M138 63.9h.7M138.7 60.8v1.3M138.7 63.3v1.3"/>
<path d="M139.3 61.3h.5l.1 .8M139.3 63.8h.5l.1 .8M139.9 61.5l-.5 .1-.1 .2 .1 .3 .5-.1M139.9 64.1h-.5l-.1 .2 .1 .3 .5-.1M178.7 75.2l-.3 .2M179.6 63.8h-.3l-.3 .2 .1 .5h.5M179.6 63.3v1.3M181.3 61.2l-.4 .3M270.9 61.2l.2 .9 .3-.6 .2 .6 .3-.9M89.6 91.4a.6 .6 0 0 0-.8 .4 .6 .6 0 0 0 .6 .7l.2-.1M91.5 96.4a.64 .64 0 0 1 .7 .6 .64 .64 0 0 1-.7 .6zM93.3 97.1h-.4l-.2 .2 .2 .3h.4"/>
<path d="M98 81.1v1l.3 .3h.2l.2-.3v-1M98.6 99.8h.6M104.4 92.5h.7M137.1 82.5a.6 .6 0 0 0-.8 .4 .6 .6 0 0 0 .6 .8l.2-.2M137.8 85a.6 .6 0 0 0-.8 .5 .6 .6 0 0 0 .6 .7l.2-.1M182 85.7h1M182.5 85.2v1M182.5 80.6h.9M182.7 83.2h.9M183 80.2v.9M183.1 82.7v1M276.9 90.8h1"/>
<path d="M65.6 117.5h1M65.6 112.4h1M65.8 109.5l-.4 .2M66.1 111.9v1M67 119.2h.8l-.4 .5 .3 .1v.6l-.1 .1-.6-.1M67.1 114.3l.5-.2 .2 .4-.8 .9h.8M67.1 109.4l.3-.3v1.2M67.1 110.3h.7M94.6 119.3a.6 .6 0 0 0-.8 .5 .6 .6 0 0 0 .6 .7l.2-.1M98.5 100.2l.4-1.3 .4 1.3M98.5 105.2l.4-1.2 .4 1.2M98.5 115.4l.4-1.3 .4 1.3"/>
<path d="M98.5 110.3l.4-1.2 .4 1.2M98.6 104.9h.6M98.6 115h.6M98.6 110h.6M129.2 100.2v1.2M130.5 100.2v1.2l-.7-1.2v1.2M141.6 102.7v1.3M177.5 103.5h.9M187.7 101.4h.7M188.6 101.6h1M189.9 101h1M61.9 124.7l-.4 .3"/>
<path d="M64.5 128.2h1M65.8 127.6h1M65.8 122.5h1M66.3 122.1v.9M94.6 124.4a.6 .6 0 0 0-.8 .4 .6 .6 0 0 0 .6 .8l.2-.2M177.4 144.6v1.3M177.4 147.2v1.2M178.8 144.6v1.3l-.8-1.3v1.3M178.8 147.2v1.2l-.8-1.2v1.2M179.1 148.5h.9M189.9 152.2v1.3M189.9 154.8v1.2"/>
<path d="M191.2 154.8v1.2l-.7-1.2v1.2M275.6 144.6v1.3l-.7-1.3v1.3M276.5 144.6l-.4 .9h.8M276.8 145v.9M277.7 147.2h.7M278 147.2v1.2M278.7 147.5l.4-.3v1.2M278.7 148.4h.8"/>
</g>
<g fill="none" stroke="#0000c2" stroke-width=".6">
<path d="M64.1 16.7a1.21 1.21 0 0 0-1.5 .1 .64 .64 0 0 0 .2 1.1l.6 .1a.7 .7 0 0 1 .4 .8 .7 .7 0 0 1-.6 .6l-1.1-.1M68 16.4l-.9 2.1h1.8M68.6 17.5l-.2 1.9M167.2 17.5l-.3 1.9M168 17.5a.84 .84 0 0 0-.9 .5M169.9 17.6a.69 .69 0 0 0-1.2 .4l.1 .3 .7 .2 .3 .1 .1 .3-.2 .4-.3 .1h-.6l-.2-.1M247.2 17.8a.7 .7 0 0 1 1.2 .1l-.2 1.5M249.5 18.5l1.4-.3v-.6l-.3-.1-.8 .1-.2 .3-.1 1.1 .1 .3 .2 .1 .9-.1M253.2 17.6a.69 .69 0 0 0-1.2 .4l.1 .3 .7 .2 .3 .1 .1 .3-.2 .4-.3 .1h-.6l-.2-.1M91.5 135.6l.4 1.9 .9-1.9M93.7 136.6l1.4-.3-.1-.5-.3-.2-.8 .2-.2 .2-.1 1.1 .1 .3 .3 .1 .8-.1M96.4 135.6l-.3 1.9"/>
<path d="M97.2 135.6a.84 .84 0 0 0-.9 .6M97.7 135.6h1.1M98.2 134.7l-.3 2.4 .1 .3 .6 .1M99.5 136.6l1.4-.3-.1-.5-.2-.2-.9 .2-.1 .2-.2 1.1 .1 .3 .3 .1 .8-.1M102.2 135.6l-.2 1.9M103 135.6a.84 .84 0 0 0-.9 .6"/>
</g>
<g fill="none" stroke="#0000c2" stroke-width=".18">
<path d="M269.7 39.6l.2-.2 .4 .2v.4l-.1 .2-.3 .1-.2-.1zM270.7 39.4h.5M271.2 39l-.3 .2v1.1M273.1 39h-.6v.6l.1-.1 .5 .1 .1 .1-.1 .5-.2 .1-.4-.1M273.5 39l.5 1.3 .4-1.3M273.8 37.4h.5M274 37v1.1l.3 .2M274.6 37.4l.2 .9 .3-.6 .2 .6 .3-.9M276 37.8l.6-.1-.1-.2-.3-.1-.2 .2v.6h.5M277.1 37.8l.5-.1v-.2l-.4-.1-.1 .2v.6h.5M278.2 37.5l.2-.1 .3 .1v.8M278.2 37.4v.9"/>
<path d="M261.6 43.5h-.4l-.2 .2 .1 .5h.5M261.6 43v1.3M262.6 43.5h-.3l-.2 .1 .1 .2 .4 .1v.3h-.5M273.6 41.9l.6-.2-.1-.2-.3-.1-.2 .2 .1 .6h.4M274.7 41.6l.2-.2 .3 .1 .1 .8M274.7 41.4v.9M276.4 41.5l-.4-.1-.2 .3 .1 .5h.5M276.4 41v1.3M277.4 41.5l-.3-.1-.2 .2 .1 .2 .4 .1v.3h-.5M25.9 117.3l.6-.1-.1-.2-.3-.1-.2 .2v.6h.5M27 116.9v.8M27.4 116.9l-.4 .2"/>
<path d="M28.2 117l-.3-.1-.2 .2 .1 .2 .4 .1v.3h-.5M30.8 112.5v1l-.5 .2M32 112.5h-.6l-.1 .6 .2-.2 .4 .1 .2 .2-.1 .4-.2 .1-.5-.1M32.6 113.6v.1M35.2 114.9v.8h.3l.2-.1M35.6 119l.2-.1 .3 .1v.8M35.7 114.9v.8M36.1 119.1l.2-.2 .3 .1v.8M36.3 115l.3-.1 .3 .2-.1 .6h-.5M36.3 114.5v1.2M37.2 108.9v.8M37.2 119l.4-.1 .2 .3-.1 .5h-.5"/>
<path d="M37.2 118.9v1.3M37.5 108.9l-.3 .2M38 108.9v.8M38.3 108.9l-.3 .2M38.4 118.5v1.1l.2 .2M38.4 115.3h.9M38.5 110.9h-.4l-.2 .2 .1 .5h.5M38.7 109.3l.6-.1-.1-.3h-.4l-.1 .1v.6h.5M38.8 114.8v.9M39 111.3l.6-.1-.1-.3h-.4l-.1 .1v.6h.5M39 119.3l.6-.1-.1-.2-.4-.1-.1 .2v.6h.5M39.8 109l.2-.1h.3v.8"/>
<path d="M39.8 108.9v.8M40.8 108.9h.4M40.9 108.4v1.1l.3 .2M41.1 110.9h.3l.2 .2v.4l-.2 .2-.3-.1-.1-.1zM42 110.9h.5M42.5 110.5l-.3 .1v1.1M42.8 106.8l.3-.4v1.3M42.8 107.7h.7M44 107.6v.1M44.9 106.4l-.3 .9h.7M45.2 106.8v.9M46.8 106.8v.8l.3 .1 .2-.1"/>
<path d="M47.3 106.8v.9M47.9 106.4v1.3M47.9 107h.7M48.6 106.4v1.3M26.8 121.3l.6-.1v-.2l-.4-.1-.2 .2 .1 .6h.5M27.8 120.9h.5M28 120.5v1.1l.3 .2M35.9 146.4l.3-.1 .2 .3v.3l-.2 .3-.3-.1-.1-.2zM36.8 146.3h.5M37 145.9v1.1l.3 .2M37.7 146.5l.2-.2 .3 .1v.8M37.7 145.9v1.3"/>
<path d="M38.7 146.7l.6-.1v-.2l-.4-.1-.2 .2 .1 .6h.5M39.6 142.4l.3-.1 .2 .2v.4l-.2 .2h-.3l-.1-.2zM39.9 146.3v.9M40.2 146.3l-.3 .3M41.2 142.4l-.4-.1-.2 .2 .1 .6h.5M41.2 141.9v1.2M41.6 140.3l.2 .8 .3-.6 .2 .6 .3-.8M41.7 142.7l.6-.1v-.2l-.4-.1-.2 .2 .1 .6h.5M42 144.4l.2-.1 .4 .1v.5l-.1 .2-.3 .1-.2-.2zM42.9 143v.1M43 140.7l.6-.1-.1-.2-.3-.1-.2 .2v.6h.5M43.2 144.3v.9"/>
<path d="M43.5 144.3l-.3 .3M44 140.7l.6-.1v-.2l-.4-.1-.2 .2 .1 .6h.5M44.5 144.4l-.4-.1-.2 .3 .1 .5h.5M44.5 143.9v1.3M45 144.7l.6-.1-.1-.2-.3-.1-.2 .2 .1 .6h.4M45.2 140.4l.2-.1 .3 .1v.7M45.2 140.3v.8M46.1 144.3v.9M46.5 144.3l-.4 .3"/>
</g>
<path d="M207.6 134.5a.94 .94 0 0 0-1.4 .4l-.1 .8 .2 .4 .3 .2 .8-.2M208.6 135.3l1.4-.2-.1-.6-.2-.1-.9 .1-.1 .3-.2 1.1 .1 .2 .3 .2 .8-.2" fill="none" stroke="#0000c2" stroke-width=".57"/>
<g fill="none" stroke="#0000c2" stroke-width=".18" stroke-dasharray=".8 .8">
<path d="M14 14.2h182.8M127 14.2v118.1M196.8 14.2v58.4M283.2 14.2h-86.4M196.8 72.6h86.4M283.2 72.6v59.7M283.2 72.6v-58.4M14 132.3v-118.1M14 132.3v54.6M107.9 132.3v54.6M175.3 132.3v31.8M196.8 132.3h-182.8"/>
<path d="M283.2 132.3h-86.4M175.3 164.1h107.9M283.2 164.1v-33M107.9 186.9h-93.9M107.9 186.9h67.4M175.3 186.9v-22.8"/>
</g>
<g fill="none" stroke="#008400" stroke-width=".18">
<path d="M26.7 32h25.4M47 32v2.5M47 39.6v3.8M57.1 32h16.6M68.6 34.5h5.1M68.6 37.1h5.1M68.6 39.6h5.1M73.7 29.5h-5.1v12.7h5.1M86.4 29.5h19M86.4 32h19M86.4 34.5h19M86.4 39.6h26.6v88.9"/>
<path d="M86.4 37.1h19M144.8 38.3h8.9M144.8 35.8h8.9M231.1 30.7h5.1M231.1 35.8h5.1M246.4 33.3h2.5M26.7 47.2h25.4M34.3 42.2v1.2h22.8M34.3 57.4v1.3h22.8M47 47.2v1.3M47 53.6v5.1M57.1 47.2h16.6"/>
<path d="M68.6 49.8h5.1M68.6 52.3h5.1M68.6 54.9h5.1M73.7 44.7h-5.1v12.7h5.1M73.7 59.9h-5.1v12.7h5.1M86.4 49.8h19M86.4 47.2h19M86.4 52.3h19M86.4 42.2h26.6M86.4 59.9h19M144.8 40.9h8.9M151.1 59.9h2.6"/>
<path d="M153.7 43.4h-6.4v1.3M166.4 59.9h2.5v5.1M226.1 49.8h7.6M226.1 47.2h7.6M226.1 52.3h7.6M226.1 59.9h7.6M226.1 57.4h7.6M226.1 54.9h7.6M248.9 49.8h5.1M248.9 47.2h5.1v12.7h-5.1M248.9 52.3h15.3v2.6M248.9 57.4h5.1"/>
<path d="M248.9 54.9h5.1M26.7 62.5h25.4M27.9 76.4v1.3h6.4M34.3 72.6v1.3h22.8M39.4 77.7h34.3M40.6 77.7v7.6M47 62.5v1.2M47 68.8v5.1M47 77.7v7.6M57.1 62.5h16.6M62.2 77.7v15.3h11.5M68.6 65h5.1"/>
<path d="M68.6 67.6h5.1M68.6 70.1h5.1M73.7 75.2h-5.1v12.7h5.1M86.4 62.5h19M86.4 65h19M86.4 77.7h19M86.4 72.6h26.6M86.4 67.6h19M86.4 70.1h26.6M151.1 62.5h2.6M151.1 65h2.6M153.7 79h-2.6v10.1"/>
<path d="M166.4 62.5h7.6M166.4 76.4h5M166.4 65h7.6v2.6M226.1 62.5h2.5M248.9 62.5h15.3M40.6 90.4v7.6M47 90.4v7.6M68.6 85.3h5.1M68.6 82.8h5.1M68.6 95.5h5.1M68.6 80.3h5.1M73.7 90.4h-5.1v17.8h5.1"/>
<path d="M73.7 98h-45.8v1.3M86.4 87.9h26.6M86.4 93h19M86.4 98h19M86.4 85.3h26.6M86.4 82.8h19M86.4 95.5h19M86.4 80.3h19M148.6 84.1h5.1M148.6 86.6h5.1M148.6 81.5h5.1M166.4 84.1h5"/>
<path d="M166.4 86.6h5M166.4 81.5h5M201.9 99.3v2.5h14v-2.5M204.5 99.3v5.1M212.1 84.1h58.4M212.1 91.7h58.4M212.1 89.1h58.4M215.9 84.1v10.1M229.9 89.1v22.9h2.5M245.1 84.1v12.7M261.6 91.7v20.3h-3.8M54.6 113.3h19.1"/>
<path d="M54.6 118.4h19.1M54.6 110.7h19.1M54.6 115.8h19.1M68.6 105.7h5.1M68.6 100.6h5.1M68.6 103.1h5.1M86.4 105.7h19M86.4 100.6h19M86.4 110.7h19M86.4 115.8h19M151.1 101.8h2.6M151.1 104.4h2.6"/>
<path d="M153.7 106.9h-2.6v1.3M166.4 106.9h2.5M166.4 101.8h2.5M166.4 104.4h2.5M229.9 106.9h2.5M257.8 106.9h3.8M54.6 120.9h19.1M54.6 126h19.1M54.6 128.5h19.1M54.6 123.4h19.1M86.4 120.9h19M86.4 126h19"/>
<path d="M245.1 122.2v2.5M22.9 153.9h26.6M27.9 153.9v1.3M38.1 153.9v2.6M44.4 153.9v2.6h5.1M74.9 153.9h2.6M74.9 159h14M82.5 153.9h12.7M88.9 153.9v12.7M141 156.5v5M199.4 156.5h5.1M199.4 153.9h5.1"/>
<path d="M199.4 146.3h5.1M199.4 148.8h5.1M256.5 153.9h6.4M256.5 146.3h6.4M256.5 148.8h6.4M27.9 167.9v7.6h61v-3.8M27.9 160.3v2.5M27.9 161.5h21.6M38.1 161.5v14M44.4 171.7v3.8M49.5 164.1h-5.1v2.5M62.2 169.2v10.1"/>
</g>
<g fill="none" stroke="#000084" stroke-width=".18">
<path d="M85.8 54.2l1.2 1.3M85.8 44.1l1.2 1.2M85.8 56.8l1.2 1.2M87 54.2l-1.2 1.3M87 44.1l-1.2 1.2M87 56.8l-1.2 1.2M85.8 74.6l1.2 1.2M87 74.6l-1.2 1.2M153.1 75.8l1.2 1.3M154.3 75.8l-1.2 1.3M165.8 78.4l1.2 1.2M167 78.4l-1.2 1.2"/>
<path d="M233.1 64.4l1.2 1.2M234.3 64.4l-1.2 1.2M248.3 64.4l1.2 1.2M249.5 64.4l-1.2 1.2M85.8 89.8l1.2 1.2M87 89.8l-1.2 1.2M153.1 98.7l1.2 1.2M153.1 96.2l1.2 1.2M154.3 98.7l-1.2 1.2M154.3 96.2l-1.2 1.2M165.8 98.7l1.2 1.2M165.8 96.2l1.2 1.2"/>
<path d="M167 98.7l-1.2 1.2M167 96.2l-1.2 1.2M211.5 93.6l1.2 1.2M212.7 93.6l-1.2 1.2M85.8 112.7l1.2 1.2M85.8 117.7l1.2 1.3M85.8 107.6l1.2 1.2M85.8 102.5l1.2 1.2M87 112.7l-1.2 1.2M87 117.7l-1.2 1.3M87 107.6l-1.2 1.2M87 102.5l-1.2 1.2"/>
<path d="M85.8 122.8l1.2 1.2M85.8 127.9l1.2 1.2M87 122.8l-1.2 1.2M87 127.9l-1.2 1.2"/>
</g>
<g fill="#008400" stroke="#008400" stroke-width=".18">
<circle cx="40.6" cy="77.7" r=".46"/>
<circle cx="47" cy="73.9" r=".46"/>
<circle cx="47" cy="77.7" r=".46"/>
<circle cx="47" cy="98" r=".46"/>
<circle cx="40.6" cy="98" r=".46"/>
<circle cx="44.4" cy="153.9" r=".46"/>
<circle cx="62.2" cy="175.5" r=".46"/>
<circle cx="38.1" cy="153.9" r=".46"/>
<circle cx="27.9" cy="153.9" r=".46"/>
<circle cx="27.9" cy="161.5" r=".46"/>
<circle cx="38.1" cy="175.5" r=".46"/>
<circle cx="44.4" cy="175.5" r=".46"/>
<circle cx="88.9" cy="159" r=".46"/>
<circle cx="88.9" cy="153.9" r=".46"/>
<circle cx="62.2" cy="77.7" r=".46"/>
<circle cx="68.6" cy="67.6" r=".46"/>
<circle cx="68.6" cy="77.7" r=".46"/>
<circle cx="68.6" cy="62.5" r=".46"/>
<circle cx="68.6" cy="54.9" r=".46"/>
<circle cx="68.6" cy="70.1" r=".46"/>
<circle cx="68.6" cy="65" r=".46"/>
<circle cx="113" cy="72.6" r=".46"/>
<circle cx="113" cy="87.9" r=".46"/>
<circle cx="113" cy="85.3" r=".46"/>
<circle cx="113" cy="42.2" r=".46"/>
<circle cx="68.6" cy="80.3" r=".46"/>
<circle cx="229.9" cy="89.1" r=".46"/>
<circle cx="245.1" cy="84.1" r=".46"/>
<circle cx="215.9" cy="84.1" r=".46"/>
<circle cx="261.6" cy="91.7" r=".46"/>
<circle cx="261.6" cy="106.9" r=".46"/>
<circle cx="168.9" cy="65" r=".46"/>
<circle cx="113" cy="70.1" r=".46"/>
<circle cx="254" cy="54.9" r=".46"/>
<circle cx="254" cy="57.4" r=".46"/>
<circle cx="254" cy="52.3" r=".46"/>
<circle cx="254" cy="49.8" r=".46"/>
<circle cx="229.9" cy="106.9" r=".46"/>
<circle cx="204.5" cy="101.8" r=".46"/>
<circle cx="34.3" cy="47.2" r=".46"/>
<circle cx="47" cy="47.2" r=".46"/>
<circle cx="47" cy="58.7" r=".46"/>
<circle cx="47" cy="62.5" r=".46"/>
<circle cx="34.3" cy="62.5" r=".46"/>
<circle cx="47" cy="43.4" r=".46"/>
<circle cx="47" cy="32" r=".46"/>
<circle cx="34.3" cy="32" r=".46"/>
<circle cx="68.6" cy="49.8" r=".46"/>
<circle cx="68.6" cy="52.3" r=".46"/>
<circle cx="68.6" cy="47.2" r=".46"/>
<circle cx="68.6" cy="34.5" r=".46"/>
<circle cx="68.6" cy="32" r=".46"/>
<circle cx="68.6" cy="37.1" r=".46"/>
<circle cx="68.6" cy="39.6" r=".46"/>
<circle cx="62.2" cy="93" r=".46"/>
<circle cx="62.2" cy="98" r=".46"/>
<circle cx="68.6" cy="95.5" r=".46"/>
<circle cx="68.6" cy="85.3" r=".46"/>
<circle cx="68.6" cy="82.8" r=".46"/>
<circle cx="68.6" cy="105.7" r=".46"/>
<circle cx="68.6" cy="103.1" r=".46"/>
<circle cx="68.6" cy="100.6" r=".46"/>
<circle cx="68.6" cy="98" r=".46"/>
</g>
<use href="#words"/>
</svg>
